VERSION 5.7 ;
  NOWIREEXTENSIONATPIN ON ;
  DIVIDERCHAR "/" ;
  BUSBITCHARS "[]" ;
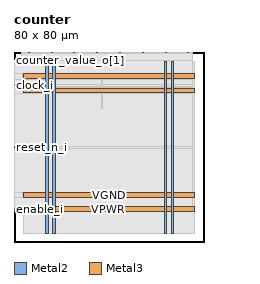
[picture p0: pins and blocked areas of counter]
MACRO counter
  CLASS BLOCK ;
  FOREIGN counter ;
  ORIGIN 0.000 0.000 ;
  SIZE 80.000 BY 80.000 ;
  PIN VGND
    DIRECTION INOUT ;
    USE GROUND ;
    PORT
      LAYER Metal2 ;
        RECT 16.340 3.560 17.340 75.820 ;
    END
    PORT
      LAYER Metal2 ;
        RECT 66.340 3.560 67.340 75.820 ;
    END
    PORT
      LAYER Metal3 ;
        RECT 3.840 18.780 75.840 20.780 ;
    END
    PORT
      LAYER Metal3 ;
        RECT 3.840 68.780 75.840 70.780 ;
    END
  END VGND
  PIN VPWR
    DIRECTION INOUT ;
    USE POWER ;
    PORT
      LAYER Metal2 ;
        RECT 13.340 3.560 14.340 75.820 ;
    END
    PORT
      LAYER Metal2 ;
        RECT 63.340 3.560 64.340 75.820 ;
    END
    PORT
      LAYER Metal3 ;
        RECT 3.840 12.780 75.840 14.780 ;
    END
    PORT
      LAYER Metal3 ;
        RECT 3.840 62.780 75.840 64.780 ;
    END
  END VPWR
  PIN clock_i
    DIRECTION INPUT ;
    USE SIGNAL ;
    ANTENNAGATEAREA 0.725400 ;
    PORT
      LAYER Metal3 ;
        RECT 0.000 65.740 0.400 66.140 ;
    END
  END clock_i
  PIN counter_value_o[0]
    DIRECTION OUTPUT ;
    USE SIGNAL ;
    ANTENNADIFFAREA 0.708600 ;
    PORT
      LAYER Metal2 ;
        RECT 6.040 79.600 6.440 80.000 ;
    END
  END counter_value_o[0]
  PIN counter_value_o[1]
    DIRECTION OUTPUT ;
    USE SIGNAL ;
    ANTENNADIFFAREA 0.708600 ;
    PORT
      LAYER Metal2 ;
        RECT 15.640 79.600 16.040 80.000 ;
    END
  END counter_value_o[1]
  PIN counter_value_o[2]
    DIRECTION OUTPUT ;
    USE SIGNAL ;
    ANTENNADIFFAREA 0.708600 ;
    PORT
      LAYER Metal2 ;
        RECT 25.240 79.600 25.640 80.000 ;
    END
  END counter_value_o[2]
  PIN counter_value_o[3]
    DIRECTION OUTPUT ;
    USE SIGNAL ;
    ANTENNADIFFAREA 0.708600 ;
    PORT
      LAYER Metal2 ;
        RECT 34.840 79.600 35.240 80.000 ;
    END
  END counter_value_o[3]
  PIN counter_value_o[4]
    DIRECTION OUTPUT ;
    USE SIGNAL ;
    ANTENNADIFFAREA 0.708600 ;
    PORT
      LAYER Metal2 ;
        RECT 44.440 79.600 44.840 80.000 ;
    END
  END counter_value_o[4]
  PIN counter_value_o[5]
    DIRECTION OUTPUT ;
    USE SIGNAL ;
    ANTENNADIFFAREA 0.708600 ;
    PORT
      LAYER Metal2 ;
        RECT 54.040 79.600 54.440 80.000 ;
    END
  END counter_value_o[5]
  PIN counter_value_o[6]
    DIRECTION OUTPUT ;
    USE SIGNAL ;
    ANTENNADIFFAREA 0.708600 ;
    PORT
      LAYER Metal2 ;
        RECT 63.640 79.600 64.040 80.000 ;
    END
  END counter_value_o[6]
  PIN counter_value_o[7]
    DIRECTION OUTPUT ;
    USE SIGNAL ;
    ANTENNADIFFAREA 0.708600 ;
    PORT
      LAYER Metal2 ;
        RECT 73.240 79.600 73.640 80.000 ;
    END
  END counter_value_o[7]
  PIN enable_i
    DIRECTION INPUT ;
    USE SIGNAL ;
    ANTENNAGATEAREA 0.180700 ;
    PORT
      LAYER Metal3 ;
        RECT 0.000 13.660 0.400 14.060 ;
    END
  END enable_i
  PIN reset_n_i
    DIRECTION INPUT ;
    USE SIGNAL ;
    ANTENNAGATEAREA 0.180700 ;
    PORT
      LAYER Metal3 ;
        RECT 0.000 39.700 0.400 40.100 ;
    END
  END reset_n_i
  OBS
      LAYER GatPoly ;
        RECT 3.840 3.630 75.840 75.750 ;
      LAYER Metal1 ;
        RECT 3.840 3.560 75.840 75.820 ;
      LAYER Metal2 ;
        RECT 3.255 79.390 5.830 79.600 ;
        RECT 6.650 79.390 15.430 79.600 ;
        RECT 16.250 79.390 25.030 79.600 ;
        RECT 25.850 79.390 34.630 79.600 ;
        RECT 35.450 79.390 44.230 79.600 ;
        RECT 45.050 79.390 53.830 79.600 ;
        RECT 54.650 79.390 63.430 79.600 ;
        RECT 64.250 79.390 73.030 79.600 ;
        RECT 73.850 79.390 74.985 79.600 ;
        RECT 3.255 76.030 74.985 79.390 ;
        RECT 3.255 13.715 13.130 76.030 ;
        RECT 14.550 13.715 16.130 76.030 ;
        RECT 17.550 13.715 63.130 76.030 ;
        RECT 64.550 13.715 66.130 76.030 ;
        RECT 67.550 13.715 74.985 76.030 ;
      LAYER Metal3 ;
        RECT 0.400 70.990 75.025 76.540 ;
        RECT 0.400 68.570 3.630 70.990 ;
        RECT 0.400 66.350 75.025 68.570 ;
        RECT 0.610 65.530 75.025 66.350 ;
        RECT 0.400 64.990 75.025 65.530 ;
        RECT 0.400 62.570 3.630 64.990 ;
        RECT 0.400 40.310 75.025 62.570 ;
        RECT 0.610 39.490 75.025 40.310 ;
        RECT 0.400 20.990 75.025 39.490 ;
        RECT 0.400 18.570 3.630 20.990 ;
        RECT 0.400 14.990 75.025 18.570 ;
        RECT 0.400 14.270 3.630 14.990 ;
        RECT 0.610 13.760 3.630 14.270 ;
      LAYER Metal4 ;
        RECT 36.860 56.135 37.060 68.185 ;
  END
END counter
END LIBRARY

